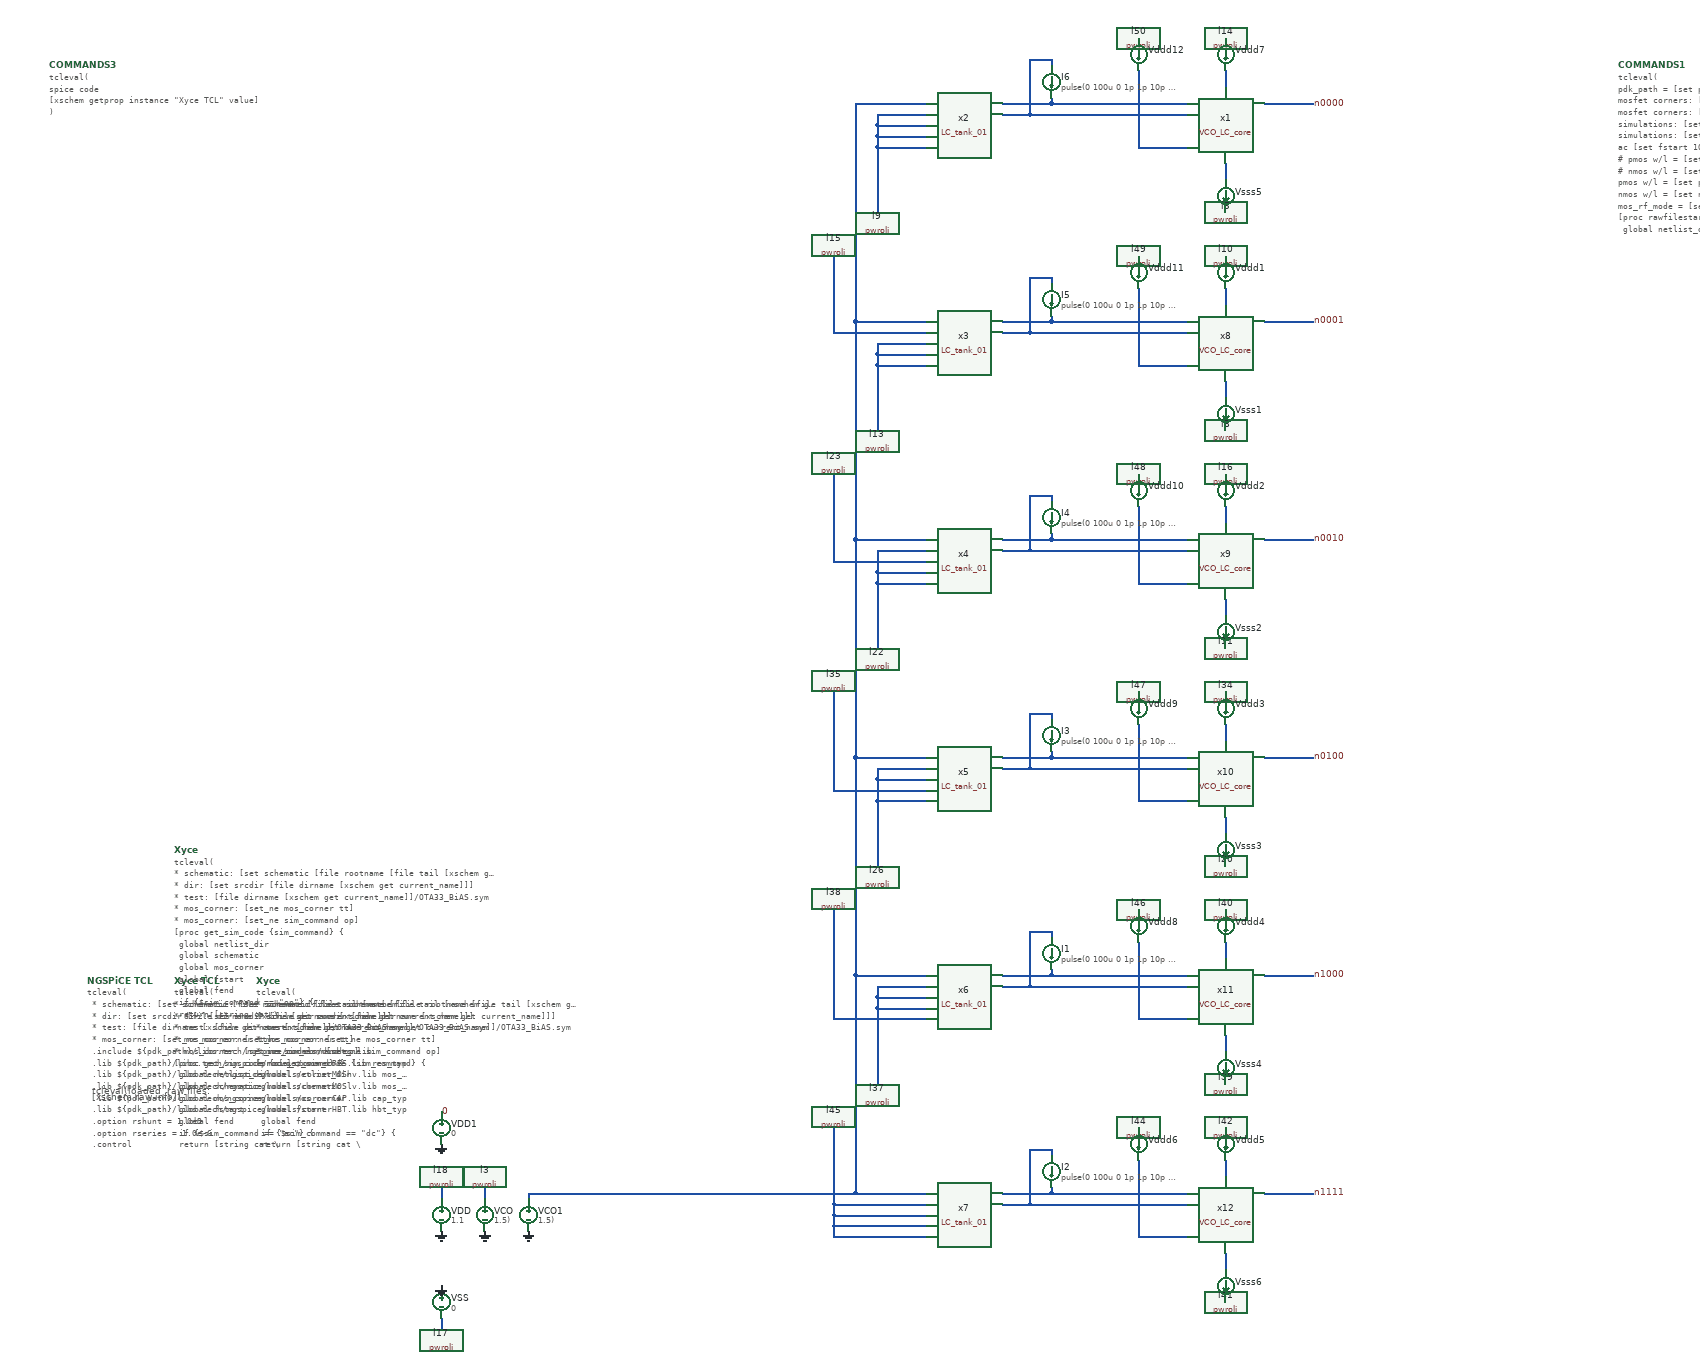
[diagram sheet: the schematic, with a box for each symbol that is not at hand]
v {xschem version=3.4.7RC file_version=1.2
*
* This file is part of XSCHEM,
* a schematic capture and Spice/Vhdl/Verilog netlisting tool for circuit
* simulation.
* Copyright (C) 1998-2023 Stefan Frederik Schippers
*
* This program is free software; you can redistribute it and/or modify
* it under the terms of the GNU General Public License as published by
* the Free Software Foundation; either version 2 of the License, or
* (at your option) any later version.
*
* This program is distributed in the hope that it will be useful,
* but WITHOUT ANY WARRANTY; without even the implied warranty of
* MERCHANTABILITY or FITNESS FOR A PARTICULAR PURPOSE.  See the
* GNU General Public License for more details.
*
* You should have received a copy of the GNU General Public License
* along with this program; if not, write to the Free Software
* Foundation, Inc., 51 Franklin Street, Fifth Floor, Boston, MA 02110-1301 USA
}
G {}
K {}
V {}
S {}
E {}
B 2 2960 -1360 4720 -80 {flags=graph
y1=-0.038
y2=1.6
ypos1=0
ypos2=2
divy=5
subdivy=4
unity=1
x1=9.3614477e-08
x2=9.4549369e-08
divx=5
subdivx=4
xlabmag=1.0
ylabmag=1.0
dataset=-1
unitx=1
logx=0
logy=0
sim_type=tran
autoload=1
rawfile=$netlist_dir/VCO_LC__TB_tran_01_tran_mostt.spice.raw
color="5 4 4 4 4 7"
node="n0000
n0001
n0010
n0100
n1000
n1111"}
T {tcleval(loaded .raw files: 
[xschem raw info])} 160 -720 0 0 0.3 0.3 {floater=true layer=16}
N 800 -290 800 -270 {
lab=VSS}
N 800 -530 800 -510 {
lab=VDD}
N 880 -530 880 -510 {
lab=VCO}
N 1600 -2500 1690 -2500 {lab=VSS}
N 1600 -2480 1690 -2480 {lab=VSS}
N 1600 -2500 1600 -2480 {lab=VSS}
N 1600 -2440 1600 -2320 {lab=VSS}
N 1600 -2460 1690 -2460 {lab=VSS}
N 1600 -2480 1600 -2460 {lab=VSS}
N 1600 -2440 1690 -2440 {lab=VSS}
N 1600 -2460 1600 -2440 {lab=VSS}
N 1600 -2080 1690 -2080 {lab=VSS}
N 1600 -2040 1600 -1920 {lab=VSS}
N 1600 -2060 1690 -2060 {lab=VSS}
N 1600 -2080 1600 -2060 {lab=VSS}
N 1600 -2040 1690 -2040 {lab=VSS}
N 1600 -2060 1600 -2040 {lab=VSS}
N 1520 -2100 1690 -2100 {lab=VDD}
N 1520 -2240 1520 -2100 {lab=VDD}
N 1520 -1840 1520 -1680 {lab=VDD}
N 1520 -640 1520 -500 {lab=VDD}
N 1520 -500 1690 -500 {lab=VDD}
N 1520 -500 1520 -480 {lab=VDD}
N 1520 -480 1690 -480 {lab=VDD}
N 1520 -480 1520 -460 {lab=VDD}
N 1520 -460 1690 -460 {lab=VDD}
N 1520 -460 1520 -440 {lab=VDD}
N 1520 -440 1690 -440 {lab=VDD}
N 1520 -1680 1690 -1680 {lab=VDD}
N 1520 -1260 1690 -1260 {lab=VDD}
N 1520 -1440 1520 -1260 {lab=VDD}
N 1520 -840 1690 -840 {lab=VDD}
N 1520 -1040 1520 -840 {lab=VDD}
N 1600 -1640 1690 -1640 {lab=VSS}
N 1600 -1640 1600 -1520 {lab=VSS}
N 1600 -1660 1600 -1640 {lab=VSS}
N 1600 -1660 1690 -1660 {lab=VSS}
N 1600 -1700 1600 -1660 {lab=VSS}
N 1600 -1700 1690 -1700 {lab=VSS}
N 1600 -1240 1600 -1120 {lab=VSS}
N 1600 -1240 1690 -1240 {lab=VSS}
N 1600 -1280 1600 -1240 {lab=VSS}
N 1600 -1280 1690 -1280 {lab=VSS}
N 1600 -1300 1600 -1280 {lab=VSS}
N 1600 -1300 1690 -1300 {lab=VSS}
N 1600 -860 1600 -720 {lab=VSS}
N 1600 -860 1690 -860 {lab=VSS}
N 1600 -880 1600 -860 {lab=VSS}
N 1600 -880 1690 -880 {lab=VSS}
N 1600 -900 1600 -880 {lab=VSS}
N 1600 -900 1690 -900 {lab=VSS}
N 1920 -2520 2170 -2520 {lab=#net1}
N 1880 -2500 2170 -2500 {lab=#net2}
N 2310 -2520 2400 -2520 {lab=n0000}
N 2240 -2580 2240 -2550 {lab=VDD}
N 2240 -2410 2240 -2380 {lab=VSS}
N 1920 -2120 2170 -2120 {lab=#net3}
N 1880 -2100 2170 -2100 {lab=#net4}
N 2310 -2120 2400 -2120 {lab=n0001}
N 2240 -2180 2240 -2150 {lab=VDD}
N 2240 -2010 2240 -1980 {lab=VSS}
N 1920 -1720 2170 -1720 {lab=#net5}
N 1880 -1700 2170 -1700 {lab=#net6}
N 2310 -1720 2400 -1720 {lab=n0010}
N 2240 -1780 2240 -1750 {lab=VDD}
N 2240 -1610 2240 -1580 {lab=VSS}
N 2310 -1320 2400 -1320 {lab=n0100}
N 2240 -1380 2240 -1350 {lab=VDD}
N 2240 -1210 2240 -1180 {lab=VSS}
N 1920 -1320 2170 -1320 {lab=#net7}
N 1880 -1300 2170 -1300 {lab=#net8}
N 1920 -920 2170 -920 {lab=#net9}
N 1880 -900 2170 -900 {lab=#net10}
N 2310 -920 2400 -920 {lab=n1000}
N 2240 -980 2240 -950 {lab=VDD}
N 2240 -810 2240 -780 {lab=VSS}
N 2310 -520 2400 -520 {lab=n1111}
N 2240 -580 2240 -550 {lab=VDD}
N 2240 -410 2240 -380 {lab=VSS}
N 1920 -520 2170 -520 {lab=#net11}
N 1880 -500 2170 -500 {lab=#net12}
N 2080 -580 2080 -440 {lab=VCO}
N 2080 -440 2170 -440 {lab=VCO}
N 2080 -980 2080 -840 {lab=VCO}
N 2080 -840 2170 -840 {lab=VCO}
N 2080 -1380 2080 -1240 {lab=VCO}
N 2080 -1240 2170 -1240 {lab=VCO}
N 2080 -1780 2080 -1640 {lab=VCO}
N 2080 -1640 2170 -1640 {lab=VCO}
N 2080 -2180 2080 -2040 {lab=VCO}
N 2080 -2040 2170 -2040 {lab=VCO}
N 2080 -2580 2080 -2440 {lab=VCO}
N 2080 -2440 2170 -2440 {lab=VCO}
N 1920 -530 1920 -520 {lab=#net11}
N 1830 -520 1920 -520 {lab=#net11}
N 1880 -600 1880 -500 {lab=#net12}
N 1830 -500 1880 -500 {lab=#net12}
N 1880 -600 1920 -600 {lab=#net12}
N 1920 -600 1920 -590 {lab=#net12}
N 1920 -930 1920 -920 {lab=#net9}
N 1880 -1000 1880 -900 {lab=#net10}
N 1880 -1000 1920 -1000 {lab=#net10}
N 1920 -1000 1920 -990 {lab=#net10}
N 1830 -920 1920 -920 {lab=#net9}
N 1830 -900 1880 -900 {lab=#net10}
N 1920 -1330 1920 -1320 {lab=#net7}
N 1880 -1400 1880 -1300 {lab=#net8}
N 1880 -1400 1920 -1400 {lab=#net8}
N 1920 -1400 1920 -1390 {lab=#net8}
N 1830 -1320 1920 -1320 {lab=#net7}
N 1830 -1300 1880 -1300 {lab=#net8}
N 1920 -1730 1920 -1720 {lab=#net5}
N 1880 -1800 1880 -1700 {lab=#net6}
N 1880 -1800 1920 -1800 {lab=#net6}
N 1920 -1800 1920 -1790 {lab=#net6}
N 1920 -2130 1920 -2120 {lab=#net3}
N 1880 -2200 1880 -2100 {lab=#net4}
N 1880 -2200 1920 -2200 {lab=#net4}
N 1920 -2200 1920 -2190 {lab=#net4}
N 1920 -2530 1920 -2520 {lab=#net1}
N 1880 -2600 1880 -2500 {lab=#net2}
N 1880 -2600 1920 -2600 {lab=#net2}
N 1920 -2600 1920 -2590 {lab=#net2}
N 1830 -1720 1920 -1720 {lab=#net5}
N 1830 -1700 1880 -1700 {lab=#net6}
N 1830 -2120 1920 -2120 {lab=#net3}
N 1830 -2100 1880 -2100 {lab=#net4}
N 1830 -2520 1920 -2520 {lab=#net1}
N 1830 -2500 1880 -2500 {lab=#net2}
N 960 -520 960 -510 {
lab=#net13}
N 1560 -520 1690 -520 {lab=#net13}
N 1560 -920 1560 -520 {lab=#net13}
N 960 -520 1560 -520 {lab=#net13}
N 1560 -920 1690 -920 {lab=#net13}
N 1560 -1320 1560 -920 {lab=#net13}
N 1560 -1320 1690 -1320 {lab=#net13}
N 1560 -1720 1560 -1320 {lab=#net13}
N 1560 -1720 1690 -1720 {lab=#net13}
N 1560 -2120 1560 -1720 {lab=#net13}
N 1560 -2120 1690 -2120 {lab=#net13}
N 1560 -2520 1560 -2120 {lab=#net13}
N 1560 -2520 1690 -2520 {lab=#net13}
C {title.sym} 160 -30 0 0 {name=l1 author="om"  net_name=true}
C {vsource.sym} 800 -480 0 0 {name=VDD value=1.1  net_name=true
lvs_ignore=open}
C {vsource.sym} 800 -320 0 0 {name=VSS value=0  net_name=true
lvs_ignore=open}
C {pwroli.sym} 800 -270 0 0 {name=l17 lab=VSS}
C {pwroli.sym} 800 -530 2 0 {name=l18 lab=VDD
}
C {gndoli.sym} 800 -450 0 0 {name=l19 lab=GND}
C {gndoli.sym} 800 -350 2 0 {name=l30 lab=GND}
C {simulator_commands_shown.sym} 2960 -2590 0 0 {name=COMMANDS1
simulator=none
only_toplevel=false 

value="tcleval(

pdk_path = [set pdk_path $\{PDK_ROOT\}/$\{PDK\}]



mosfet corners: [set corners [list tt ss ff sf fs]]
mosfet corners: [set corners [list tt]]

simulations: [set simulations [list op dc dc_zoom ac tran]]
simulations: [set simulations [list op tran]]


ac [set fstart 10e6]..[set fend 101e9]Hz;

# pmos w/l = [set pw 2u]/[set pl 1u] dont work for TCL
# nmos w/l = [set nw 1u]/[set nl 1u] dont work for TCL
pmos w/l = [set pw 10e-6]/[set pl .13e-6]
nmos w/l = [set nw 5e-6]/[set nl .13e-6]

mos_rf_mode = [set mos_rf_mode 1]


[proc rawfilestart \{\} \{
  global netlist_dir
  return $\{netlist_dir\}/[file rootname [file tail [xschem get current_name]]]
\}]

[proc sim_is_none \{\} \{ return 0\}] #proc to ignore "simulator=none" evaluation for ngspice

.raw-file path and namebase: [rawfilestart] 
)"}
C {simulator_commands.sym} 150 -910 0 0 {name="NGSPiCE TCL"
simulator=ngspice
only_toplevel=true 

value="tcleval(
    * schematic: [set schematic [file rootname [file tail [xschem get current_name]]]]
    * dir: [set srcdir [file dirname [xschem get current_name]]]
    * test: [file dirname [xschem get current_name]]/OTA33_BiAS.sym

    * mos_corner: [set_ne mos_corner tt]

    .include $\{pdk_path\}/libs.tech/ngspice/models/diodes.lib 

    .lib $\{pdk_path\}/libs.tech/ngspice/models/cornerRES.lib     res_typ
    .lib $\{pdk_path\}/libs.tech/ngspice/models/cornerMOShv.lib   mos_$\{mos_corner\}
    .lib $\{pdk_path\}/libs.tech/ngspice/models/cornerMOSlv.lib   mos_$\{mos_corner\}
    .lib $\{pdk_path\}/libs.tech/ngspice/models/cornerCAP.lib     cap_typ
    .lib $\{pdk_path\}/libs.tech/ngspice/models/cornerHBT.lib     hbt_typ


    .option rshunt = 1.0e9
    .option rseries = 1.0e-6

    .control
        pre_osdi $\{pdk_path\}/libs.tech/ngspice/openvaf/psp103_nqs.osdi
        pre_set strict_errorhandling **destroys ac simulation with .option savecurrents

        unset ngdebug

        .option maxwarns

        .param nw=$nw
        .param nl=$nl
        .param pw=$pw
        .param pl=$pl

        .param iset=1u

        save all
        op
        write $\{netlist_dir\}/$\{schematic\}_mos$\{mos_corner\}.raw
        write $\{netlist_dir\}/$\{schematic\}_dc_mos$\{mos_corner\}.raw
        write $\{netlist_dir\}/$\{schematic\}_zoom_dc_mos$\{mos_corner\}.raw
        write $\{netlist_dir\}/$\{schematic\}_ac_mos$\{mos_corner\}.raw
        write $\{netlist_dir\}/$\{schematic\}_temp_mos$\{mos_corner\}.raw

        set appendwrite

        [return \{* foreach begin\}]
        [
            set code \{\};
            foreach i $i_list \{
                append code \\" 
                alterparam iset = $i 
                reset 
                save all 
                dc vminus -3 3 0.1 
                write $\{netlist_dir\}/$\{schematic\}_dc_mos$\{mos_corner\}.raw 
                dc vminus -10m 10m 100u 
                write $\{netlist_dir\}/$\{schematic\}_zoom_dc_mos$\{mos_corner\}.raw 
                ac dec 10 $fstart $fend 
                remzerovec 
                write $\{netlist_dir\}/$\{schematic\}_ac_mos$\{mos_corner\}.raw 
                dc temp -40 160 20 
                write $\{netlist_dir\}/$\{schematic\}_temp_mos$\{mos_corner\}.raw 
                tran 1n 77u
                write $\{netlist_dir\}/$\{schematic\}_mos$\{mos_corner\}.raw
                \\";
            \}
            return $code;
        ]
        [return \{* end\}]

        quit 
    .endc
)
"
spice_ignore=true}
C {launcher.sym} 220 -240 0 0 {name=h12
descr="load waves"
tclcommand="
proc load_wavefoarms \{\} \{

    global netlist_dir
    global mos_corner

    proc get_raw_data_info_txt \{\} \{
        set data \{\}
        foreach \{i f t\} [lrange [xschem raw info] 2 end] \{
            append data \\"$i: $\{f\}\\\\n\\"
            xschem raw switch $f $t
            for \{set j 0\} \{$j < [xschem raw_query datasets]\} \{incr j\} \{
                set points [xschem raw_query points $j]
                append data \\"  [string toupper $t] set: $j $\{points\} pts\\\\n\\"
            \}
        \}
        puts [set data]

        return [set data]
    \}
    set_ne mos_corner tt
    set schematic [file rootname [file tail [xschem get current_name]]]
    xschem raw_clear;
    xschem annotate_op $\{netlist_dir\}/$\{schematic\}_mos$\{mos_corner\}.spice.raw

    return [get_raw_data_info_txt]
\}

set raw_file_data_detailed [load_wavefoarms]

xschem redraw
"
}
C {simulator_commands_shown.sym} 80 -2590 0 0 {name=COMMANDS3
simulator=none
only_toplevel=false 

value="tcleval(

spice code

[xschem getprop instance \\"Xyce TCL\\" value]
)"}
C {simulator_commands.sym} 310 -910 0 0 {name="Xyce TCL"
simulator=xyce
only_toplevel=true 

value="tcleval(
* schematic: [set schematic [file rootname [file tail [xschem get current_name]]]]
* dir:       [set srcdir [file dirname [xschem get current_name]]]
* test:      [file dirname [xschem get current_name]]/OTA33_BiAS.sym

* mos_corner: [set_ne mos_corner tt]
* mos_corner: [set_ne sim_command op]


[proc get_sim_code \{sim_command\} \{

    global netlist_dir
    global schematic
    global mos_corner

    global fstart
    global fend

    if \{$sim_command == \\"ac\\"\} \{
        return [string cat \\\\
                \\".ac dec 100 $fstart $fend \\\\\\n\\" \\\\
                \\".print ac format=raw v(*) i(*)\\" \\\\
            ]
    \} elseif \{$sim_command == \\"tran\\"\} \{
        return [string cat \\\\
                \\".tran 10p 10n \\\\\\n\\"\\\\
                \\".print tran format=raw v(*) i(*)\\" \\\\
            ]
    \} else \{
        puts    \\"error: get_sim_code\{\}; simulation not implemented $sim_command\\\\\\n\\"
        return  \\"error: simulation not implemented $sim_command\\\\\\n\\"
    \}
\}]



.option temp=27


.lib $\{pdk_path\}/libs.tech/xyce/models/cornerRES.lib     res_typ
.lib $\{pdk_path\}/libs.tech/xyce/models/cornerCAP.lib     cap_typ

.lib $\{pdk_path\}/libs.tech/xyce/models/cornerMOShv.lib   mos_$\{mos_corner\}
.lib $\{pdk_path\}/libs.tech/xyce/models/cornerMOSlv.lib   mos_$\{mos_corner\}
.lib $\{pdk_path\}/libs.tech/xyce/models/cornerHBT.lib     hbt_typ

.param nw=$nw
.param nl=$nl
.param pw=$pw
.param pl=$pl
.param iset=0

* .step dec iset 10u 100u 3

[get_sim_code $sim_command]

)
"
spice_ignore=true}
C {gndoli.sym} 800 -610 0 0 {name=l25 lab=GND}
C {lab_pin.sym} 800 -670 0 1 {name=p8 lab=0  net_name=true}
C {simulator_commands.sym} 310 -1150 0 0 {name=Xyce TCL1
simulator=xyce
only_toplevel=true 

value="tcleval(
* schematic: [set schematic [file rootname [file tail [xschem get current_name]]]]
* dir:       [set srcdir [file dirname [xschem get current_name]]]
* test:      [file dirname [xschem get current_name]]/OTA33_BiAS.sym

* mos_corner: [set_ne mos_corner tt]
* mos_corner: [set_ne sim_command op]


[proc get_sim_code \{sim_command\} \{

    global netlist_dir
    global schematic
    global mos_corner

    global fstart
    global fend

    if \{$sim_command == \\"op\\"\} \{
        return [string cat \\\\
                \\".op \\\\\\n\\" \\\\
                \\".print op -format=raw -file=$\{schematic\}_$\{sim_command\}_mos$\{mos_corner\}.raw  v(*) i(*)\\" \\\\
            ]
    \} elseif \{$sim_command == \\"dc\\"\} \{
        return [string cat \\\\
                \\".dc vminus -3 3 0.1 \\\\\\n\\" \\\\
                \\".print dc -format=raw -file=$\{schematic\}_$\{sim_command\}_mos$\{mos_corner\}.raw  v(*) i(*)\\" \\\\
            ]
    \} elseif \{$sim_command == \\"dc_zoom\\"\} \{
        return [string cat \\\\
                \\".dc vminus -10m 10m 100u \\\\\\n\\" \\\\
                \\".print dc -format=raw -file=$\{netlist_dir\}/$\{schematic\}_$\{sim_command\}_mos$\{mos_corner\}.raw  v(*) i(*)\\" \\\\
            ]
    \} elseif \{$sim_command == \\"ac\\"\} \{
        return [string cat \\\\
                \\".ac dec 10 $fstart $fend \\\\\\n\\" \\\\
                \\".print ac -format=raw -file=$\{netlist_dir\}/$\{schematic\}_$\{sim_command\}_mos$\{mos_corner\}.raw  v(*) i(*)\\" \\\\
            ]
    \} elseif \{$sim_command == \\"tran\\"\} \{
        return [string cat \\\\
                \\".tran 1n 77u \\\\\\n\\" \\\\
                \\".print tran -format=raw -file=$\{netlist_dir\}/$\{schematic\}_$\{sim_command\}_mos$\{mos_corner\}.raw  v(*) i(*)\\" \\\\
            ]
    \} else \{
        puts    \\"error: get_sim_code\{\}; simulation not implemented $sim_command\\\\\\n\\"
        return  \\"error: simulation not implemented $sim_command\\\\\\n\\"
    \}
\}]



.option temp=27

.lib $\{pdk_path\}/libs.tech/xyce/models/cornerMOShv.lib   mos_$\{mos_corner\}
.lib $\{pdk_path\}/libs.tech/xyce/models/cornerMOSlv.lib   mos_$\{mos_corner\}
.lib $\{pdk_path\}/libs.tech/xyce/models/cornerHBT.lib     hbt_typ

.param nw=$nw
.param nl=$nl
.param pw=$pw
.param pl=$pl
.param iset=0

.step dec iset 1u 10u 3

[get_sim_code $sim_command]

)
"
spice_ignore=true}
C {launcher.sym} 220 -360 0 0 {name=h2
descr="xschem annotate_op"
tclcommand="
xschem raw_clear
xschem annotate_op $\{netlist_dir\}/$\{schematic\}_mos$\{mos_corner\}.spice.raw
"
}
C {launcher.sym} 220 -400 0 0 {
descr="xyce netlist simulate corners ALL" 

tclcommand="

    proc simulate_and_plot \{corners load_the_plots\} \{

	global netlist_dir
	global execute
	global mos_corner
	global sim_command
	global simulations

        set schematic [file rootname [file tail [xschem get schname 0]]]

        foreach corner $corners \{ 
            set mos_corner $\{corner\};
            foreach sim $simulations \{ 

                set sim_command $sim;

                if \{$\{sim\} == \{op\}\} \{
                    xschem netlist $\{netlist_dir\}/$\{schematic\}_mos$\{corner\}.spice
                \} else \{
                    xschem netlist $\{netlist_dir\}/$\{schematic\}_$\{sim\}_mos$\{corner\}.spice
                \}
            \}
        \}

        puts netlists_written;

        foreach corner $corners \{ 
            foreach sim $simulations \{

                if \{$\{sim\} == \{op\}\} \{
                    xschem set netlist_name $\{schematic\}_mos$\{corner\}.spice
                \} else \{
                    xschem set netlist_name $\{schematic\}_$\{sim\}_mos$\{corner\}.spice
                \}

                set id_$\{sim\}_$\{corner\} [simulate ]
            \}
        \}

        puts sims_started;

        while \{[llength [get_running_cmds]]\} \{

            puts -nonewline .; flush stdout;

            delay 99;
        \}

        if \{$\{load_the_plots\}\} \{
            xschem raw_clear;
            xschem annotate_op $\{netlist_dir\}/$\{schematic\}_mostt.spice.raw
        \}

        puts done

    \}


    xschem set netlist_type spice
    set lvs_ignore 0
    set lvs_netlist 0
    set spiceprefix 1

    simulate_and_plot $\{corners\} true
"
}
C {simulator_commands.sym} 460 -910 0 0 {name=Xyce TCL1
simulator=xyce
only_toplevel=true 

value="tcleval(
* schematic: [set schematic [file rootname [file tail [xschem get current_name]]]]
* dir:       [set srcdir [file dirname [xschem get current_name]]]
* test:      [file dirname [xschem get current_name]]/OTA33_BiAS.sym

* mos_corner: [set_ne mos_corner tt]
* mos_corner: [set_ne sim_command op]


[proc get_sim_code \{sim_command\} \{

    global netlist_dir
    global schematic
    global mos_corner

    global fstart
    global fend

    if \{$sim_command == \\"dc\\"\} \{
        return [string cat \\\\
                \\".dc VDD .8 1.5 .1 \\\\\\n\\" \\\\
                \\".print dc format=raw v(*) i(*)\\"\\\\
            ]
    \} elseif \{$sim_command == \\"op\\"\} \{
        return [string cat \\\\
                \\".op\\\\\\n\\"\\\\
                \\".print dc format=raw v(*) i(*)\\"\\\\
            ]
    \} elseif \{$sim_command == \\"dc_zoom\\"\} \{
        return [string cat \\\\
                \\".dc vminus -10m 10m 100u \\\\\\n\\" \\\\
                \\".print dc format=raw v(*) i(*)\\" \\\\
            ]
    \} elseif \{$sim_command == \\"ac\\"\} \{
        return [string cat \\\\
                \\"* .step vco 0 1.8 .1 \\\\\\n\\" \\\\
                \\".ac dec 111 $fstart $fend \\\\\\n\\" \\\\
                \\".print ac format=raw v(*) i(*)\\" \\\\
            ]
    \} elseif \{$sim_command == \\"tran\\"\} \{
        return [string cat \\\\
                \\".tran 10p 100n \\\\\\n\\"\\\\
                \\".print tran format=raw v(*) i(*)\\" \\\\
            ]
    \} else \{
        puts    \\"error: get_sim_code\{\}; simulation not implemented $sim_command\\\\\\n\\"
        return  \\"error: simulation not implemented $sim_command\\\\\\n\\"
    \}
\}]



.option temp=27


.lib $\{pdk_path\}/libs.tech/xyce/models/cornerRES.lib     res_typ
.lib $\{pdk_path\}/libs.tech/xyce/models/cornerCAP.lib     cap_typ

.lib $\{pdk_path\}/libs.tech/xyce/models/cornerMOShv.lib   mos_$\{mos_corner\}
.lib $\{pdk_path\}/libs.tech/xyce/models/cornerMOSlv.lib   mos_$\{mos_corner\}
.lib $\{pdk_path\}/libs.tech/xyce/models/cornerHBT.lib     hbt_typ

.param nw=$nw
.param nl=$nl
.param pw=$pw
.param pl=$pl
.param iset=0


[get_sim_code $sim_command]

)
"}
C {vsource.sym} 800 -640 0 0 {name=VDD1 value=0  net_name=true
lvs_ignore=open}
C {vsource.sym} 880 -480 0 0 {name=VCO value="1.5)"  net_name=true
lvs_ignore=open}
C {pwroli.sym} 880 -530 2 0 {name=l3 lab=VCO
}
C {gndoli.sym} 880 -450 0 0 {name=l4 lab=GND}
C {LC_VCO/LC_tank_01.sym} 1760 -2480 0 0 {name=x2}
C {pwroli.sym} 1600 -2320 0 0 {name=l9 lab=VSS}
C {LC_VCO/LC_tank_01.sym} 1760 -2080 0 0 {name=x3}
C {pwroli.sym} 1600 -1920 0 0 {name=l13 lab=VSS}
C {pwroli.sym} 1520 -2240 2 0 {name=l15 lab=VDD
}
C {LC_VCO/LC_tank_01.sym} 1760 -1680 0 0 {name=x4}
C {LC_VCO/LC_tank_01.sym} 1760 -1280 0 0 {name=x5}
C {pwroli.sym} 1600 -1520 0 0 {name=l22 lab=VSS}
C {pwroli.sym} 1520 -1840 2 0 {name=l23 lab=VDD
}
C {LC_VCO/LC_tank_01.sym} 1760 -880 0 0 {name=x6}
C {pwroli.sym} 1600 -1120 0 0 {name=l26 lab=VSS}
C {pwroli.sym} 1520 -1440 2 0 {name=l35 lab=VDD
}
C {LC_VCO/LC_tank_01.sym} 1760 -480 0 0 {name=x7}
C {pwroli.sym} 1600 -720 0 0 {name=l37 lab=VSS}
C {pwroli.sym} 1520 -1040 2 0 {name=l38 lab=VDD
}
C {pwroli.sym} 1520 -640 2 0 {name=l45 lab=VDD
}
C {LC_VCO/VCO_LC_core.sym} 2240 -2480 0 0 {name=x1}
C {pwroli.sym} 2240 -2320 0 1 {name=l5 lab=VSS}
C {ammeter.sym} 2240 -2350 0 1 {name=Vsss5 
savecurrent=true
lvs_ignore=short}
C {pwroli.sym} 2240 -2640 2 0 {name=l14 lab=VDD
}
C {ammeter.sym} 2240 -2610 0 0 {name=Vddd7
savecurrent=true
lvs_ignore=short}
C {lab_pin.sym} 2400 -2520 0 1 {name=p1 sig_type=std_logic lab=n0000}
C {LC_VCO/VCO_LC_core.sym} 2240 -2080 0 0 {name=x8}
C {pwroli.sym} 2240 -1920 0 1 {name=l8 lab=VSS}
C {ammeter.sym} 2240 -1950 0 1 {name=Vsss1 
savecurrent=true
lvs_ignore=short}
C {pwroli.sym} 2240 -2240 2 0 {name=l10 lab=VDD
}
C {ammeter.sym} 2240 -2210 0 0 {name=Vddd1
savecurrent=true
lvs_ignore=short}
C {lab_pin.sym} 2400 -2120 0 1 {name=p2 sig_type=std_logic lab=n0001}
C {LC_VCO/VCO_LC_core.sym} 2240 -1680 0 0 {name=x9}
C {pwroli.sym} 2240 -1520 0 1 {name=l11 lab=VSS}
C {ammeter.sym} 2240 -1550 0 1 {name=Vsss2 
savecurrent=true
lvs_ignore=short}
C {pwroli.sym} 2240 -1840 2 0 {name=l16 lab=VDD
}
C {ammeter.sym} 2240 -1810 0 0 {name=Vddd2
savecurrent=true
lvs_ignore=short}
C {lab_pin.sym} 2400 -1720 0 1 {name=p3 sig_type=std_logic lab=n0010}
C {LC_VCO/VCO_LC_core.sym} 2240 -1280 0 0 {name=x10}
C {pwroli.sym} 2240 -1120 0 1 {name=l20 lab=VSS}
C {ammeter.sym} 2240 -1150 0 1 {name=Vsss3 
savecurrent=true
lvs_ignore=short}
C {pwroli.sym} 2240 -1440 2 0 {name=l34 lab=VDD
}
C {ammeter.sym} 2240 -1410 0 0 {name=Vddd3
savecurrent=true
lvs_ignore=short}
C {lab_pin.sym} 2400 -1320 0 1 {name=p4 sig_type=std_logic lab=n0100}
C {LC_VCO/VCO_LC_core.sym} 2240 -880 0 0 {name=x11}
C {pwroli.sym} 2240 -720 0 1 {name=l39 lab=VSS}
C {ammeter.sym} 2240 -750 0 1 {name=Vsss4 
savecurrent=true
lvs_ignore=short}
C {pwroli.sym} 2240 -1040 2 0 {name=l40 lab=VDD
}
C {ammeter.sym} 2240 -1010 0 0 {name=Vddd4
savecurrent=true
lvs_ignore=short}
C {lab_pin.sym} 2400 -920 0 1 {name=p5 sig_type=std_logic lab=n1000}
C {LC_VCO/VCO_LC_core.sym} 2240 -480 0 0 {name=x12}
C {pwroli.sym} 2240 -320 0 1 {name=l41 lab=VSS}
C {ammeter.sym} 2240 -350 0 1 {name=Vsss6 
savecurrent=true
lvs_ignore=short}
C {pwroli.sym} 2240 -640 2 0 {name=l42 lab=VDD
}
C {ammeter.sym} 2240 -610 0 0 {name=Vddd5
savecurrent=true
lvs_ignore=short}
C {lab_pin.sym} 2400 -520 0 1 {name=p6 sig_type=std_logic lab=n1111}
C {pwroli.sym} 2080 -640 2 0 {name=l44 lab=VCO
}
C {ammeter.sym} 2080 -610 0 0 {name=Vddd6
savecurrent=true
lvs_ignore=short}
C {pwroli.sym} 2080 -1040 2 0 {name=l46 lab=VCO
}
C {ammeter.sym} 2080 -1010 0 0 {name=Vddd8
savecurrent=true
lvs_ignore=short}
C {pwroli.sym} 2080 -1440 2 0 {name=l47 lab=VCO
}
C {ammeter.sym} 2080 -1410 0 0 {name=Vddd9
savecurrent=true
lvs_ignore=short}
C {pwroli.sym} 2080 -1840 2 0 {name=l48 lab=VCO
}
C {ammeter.sym} 2080 -1810 0 0 {name=Vddd10
savecurrent=true
lvs_ignore=short}
C {pwroli.sym} 2080 -2240 2 0 {name=l49 lab=VCO
}
C {ammeter.sym} 2080 -2210 0 0 {name=Vddd11
savecurrent=true
lvs_ignore=short}
C {pwroli.sym} 2080 -2640 2 0 {name=l50 lab=VCO
}
C {ammeter.sym} 2080 -2610 0 0 {name=Vddd12
savecurrent=true
lvs_ignore=short}
C {isource.sym} 1920 -560 0 0 {name=I2 value="pulse(0 100u 0 1p 1p 10p 1)"
lvs_ignore=open}
C {isource.sym} 1920 -960 0 0 {name=I1 value="pulse(0 100u 0 1p 1p 10p 1)"
lvs_ignore=open}
C {isource.sym} 1920 -1360 0 0 {name=I3 value="pulse(0 100u 0 1p 1p 10p 1)"
lvs_ignore=open}
C {isource.sym} 1920 -1760 0 0 {name=I4 value="pulse(0 100u 0 1p 1p 10p 1)"
lvs_ignore=open}
C {isource.sym} 1920 -2160 0 0 {name=I5 value="pulse(0 100u 0 1p 1p 10p 1)"
lvs_ignore=open}
C {isource.sym} 1920 -2560 0 0 {name=I6 value="pulse(0 100u 0 1p 1p 10p 1)"
lvs_ignore=open}
C {vsource.sym} 960 -480 0 0 {name=VCO1 value="1.5)"  net_name=true
lvs_ignore=open}
C {gndoli.sym} 960 -450 0 0 {name=l6 lab=GND}
C {launcher.sym} 380 -560 0 0 {name=h1
descr="write LVS netlist"
tclcommand="
	xschem set netlist_type spice
	set lvs_ignore 1
	set lvs_netlist 1
	set spiceprefix 0
	set last_local_netlist_dir $local_netlist_dir
	set local_netlist_dir 0
	xschem netlist [xschem get current_name].cdl
	set local_netlist_dir $last_local_netlist_dir

"
}
